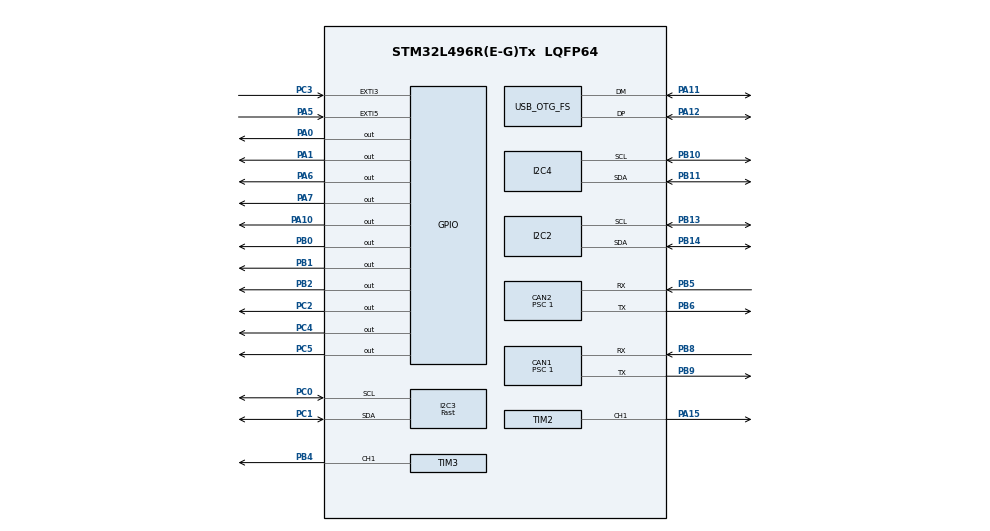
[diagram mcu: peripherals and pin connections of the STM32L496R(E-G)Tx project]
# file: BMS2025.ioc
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CAN1.BS1=CAN_BS1_2TQ
CAN1.CalculateBaudRate=500000
CAN1.CalculateTimeBit=2000
CAN1.CalculateTimeQuantum=500.0
CAN1.Prescaler=1
CAN2.BS1=CAN_BS1_2TQ
CAN2.CalculateBaudRate=500000
CAN2.CalculateTimeBit=2000
CAN2.CalculateTimeQuantum=500.0
CAN2.Prescaler=1
FREERTOS.Tasks01=defaultTask,24,128,StartDefaultTask,Default,NULL,Dynamic,NULL,NULL;Voltage_Monitor,32,128,StartTask02,Default,NULL,Dynamic,NULL,NULL;Temp_Monitoring,40,128,StartTask03,Default,NULL,Dynamic,NULL,NULL;Current_Monitor,24,256,StartTask04,Default,NULL,Dynamic,NULL,NULL;Battery_Data_Tr,32,128,StartTask05,Default,NULL,Dynamic,NULL,NULL;Update_Fan_Spee,32,128,StartTask06,Default,NULL,Dynamic,NULL,NULL
FREERTOS.configTOTAL_HEAP_SIZE=5000
FREERTOS.configUSE_NEWLIB_REENTRANT=1
I2C2.Timing=0x00000508
I2C3.I2C_Speed_Mode=I2C_Fast
I2C3.Timing=0x00000000
I2C4.Timing=0x00000508
Mcu.Family=STM32L4
Mcu.Name=STM32L496R(E-G)Tx
Mcu.Package=LQFP64
NVIC.CAN1_RX0_IRQn=true\:5\:0\:false\:false\:true\:true\:true\:true\:true
NVIC.EXTI3_IRQn=true\:5\:0\:false\:false\:true\:true\:true\:true\:true
NVIC.EXTI9_5_IRQn=true\:5\:0\:false\:false\:true\:true\:true\:true\:true
NVIC.OTG_FS_IRQn=true\:5\:0\:false\:false\:true\:true\:false\:true\:true
NVIC.PriorityGroup=NVIC_PRIORITYGROUP_4
NVIC.TIM1_UP_TIM16_IRQn=true\:15\:0\:false\:false\:true\:false\:false\:true\:true
NVIC.TimeBase=TIM1_UP_TIM16_IRQn
NVIC.TimeBaseIP=TIM1
PA0.Signal=GPIO_Output
PA1.Signal=GPIO_Output
PA10.Signal=GPIO_Output
PA11.Mode=Device_Only
PA11.Signal=USB_OTG_FS_DM
PA12.Mode=Device_Only
PA12.Signal=USB_OTG_FS_DP
PA13\ (JTMS/SWDIO).Mode=Serial_Wire
PA13\ (JTMS/SWDIO).Signal=SYS_JTMS-SWDIO
PA14\ (JTCK/SWCLK).Mode=Serial_Wire
PA14\ (JTCK/SWCLK).Signal=SYS_JTCK-SWCLK
PA15\ (JTDI).Signal=S_TIM2_CH1
PA5.Signal=GPXTI5
PA6.Signal=GPIO_Output
PA7.Signal=GPIO_Output
PB0.Signal=GPIO_Output
PB1.Signal=GPIO_Output
PB10.Mode=I2C
PB10.Signal=I2C4_SCL
PB11.Mode=I2C
PB11.Signal=I2C4_SDA
PB13.Mode=I2C
PB13.Signal=I2C2_SCL
PB14.Mode=I2C
PB14.Signal=I2C2_SDA
PB2.Signal=GPIO_Output
PB4\ (NJTRST).Signal=S_TIM3_CH1
PB5.Mode=CAN_Activate
PB5.Signal=CAN2_RX
PB6.Mode=CAN_Activate
PB6.Signal=CAN2_TX
PB8.Mode=CAN_Activate
PB8.Signal=CAN1_RX
PB9.Mode=CAN_Activate
PB9.Signal=CAN1_TX
PC0.Mode=I2C
PC0.Signal=I2C3_SCL
PC1.Mode=I2C
PC1.Signal=I2C3_SDA
PC2.Signal=GPIO_Output
PC3.Signal=GPXTI3
PC4.Signal=GPIO_Output
PC5.Signal=GPIO_Output
ProjectManager.HeapSize=0x200
ProjectManager.StackSize=0x400
ProjectManager.TargetToolchain=STM32CubeIDE
RCC.ADCFreq_Value=192000000
RCC.AHBFreq_Value=16000000
RCC.APB1CLKDivider=RCC_HCLK_DIV8
RCC.APB1Freq_Value=2000000
RCC.APB1TimFreq_Value=4000000
RCC.APB2Freq_Value=16000000
RCC.APB2TimFreq_Value=16000000
RCC.CK48CLockSelection=RCC_USBCLKSOURCE_HSI48
RCC.CortexFreq_Value=16000000
RCC.HCLKFreq_Value=16000000
RCC.HSE_VALUE=16000000
RCC.HSI48_VALUE=48000000
RCC.HSICalibrationValue=64
RCC.HSI_VALUE=16000000
RCC.LSE_VALUE=32768
RCC.MSICalibrationValue=1
RCC.MSI_VALUE=4000000
RCC.PLLN=40
RCC.PLLSAI1N=24
RCC.PLLSourceVirtual=RCC_PLLSOURCE_HSI
RCC.SYSCLKFreq_VALUE=16000000
RCC.SYSCLKSource=RCC_SYSCLKSOURCE_HSI
RCC.USBFreq_Value=48000000
RCC.VCOOutputFreq_Value=640000000
SH.S_TIM2_CH1.0=TIM2_CH1,PWM Generation1 CH1
SH.S_TIM3_CH1.0=TIM3_CH1,PWM Generation1 CH1
TIM2.Channel-PWM\ Generation1\ CH1=TIM_CHANNEL_1
TIM2.Period=40-1
TIM2.Prescaler=4-1
TIM3.Channel-PWM\ Generation1\ CH1=TIM_CHANNEL_1
TIM3.Period=40-1
TIM3.Prescaler=4-1
USB_DEVICE.CLASS_NAME_FS=CDC
USB_DEVICE.VirtualMode=Cdc
USB_DEVICE.VirtualModeFS=Cdc_FS
USB_OTG_FS.VirtualMode=Device_Only
VP_FREERTOS_VS_CMSIS_V2.Mode=CMSIS_V2
VP_SYS_VS_tim1.Mode=TIM1
VP_USB_DEVICE_VS_USB_DEVICE_CDC_FS.Mode=CDC_FS
board=custom

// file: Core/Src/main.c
/* USER CODE BEGIN Header */
/**
  ******************************************************************************
  * @file           : main.c
  * @brief          : Main program body
  ******************************************************************************
  * @attention
  *
  * Copyright (c) 2025 STMicroelectronics.
  * All rights reserved.
  *
  * This software is licensed under terms that can be found in the LICENSE file
  * in the root directory of this software component.
  * If no LICENSE file comes with this software, it is provided AS-IS.
  *
  ******************************************************************************
  */
/* USER CODE END Header */
#include "main.h"
#include "cmsis_os.h"

CAN_HandleTypeDef hcan1;
CAN_HandleTypeDef hcan2;

I2C_HandleTypeDef hi2c2;
I2C_HandleTypeDef hi2c3;
I2C_HandleTypeDef hi2c4;

TIM_HandleTypeDef htim2;
TIM_HandleTypeDef htim3;

HCD_HandleTypeDef hhcd_USB_OTG_FS;

/* Definitions for defaultTask */
osThreadId_t defaultTaskHandle;
const osThreadAttr_t defaultTask_attributes = {
  .name = "defaultTask",
  .stack_size = 128 * 4,
  .priority = (osPriority_t) osPriorityNormal,
};
/* Definitions for Voltage_Monitor */
osThreadId_t Voltage_MonitorHandle;
const osThreadAttr_t Voltage_Monitor_attributes = {
  .name = "Voltage_Monitor",
  .stack_size = 128 * 4,
  .priority = (osPriority_t) osPriorityAboveNormal,
};
/* Definitions for Temp_Monitoring */
osThreadId_t Temp_MonitoringHandle;
const osThreadAttr_t Temp_Monitoring_attributes = {
  .name = "Temp_Monitoring",
  .stack_size = 128 * 4,
  .priority = (osPriority_t) osPriorityHigh,
};
/* Definitions for Current_Monitor */
osThreadId_t Current_MonitorHandle;
const osThreadAttr_t Current_Monitor_attributes = {
  .name = "Current_Monitor",
  .stack_size = 128 * 4,
  .priority = (osPriority_t) osPriorityNormal,
};
/* Definitions for Battery_Data_Tr */
osThreadId_t Battery_Data_TrHandle;
const osThreadAttr_t Battery_Data_Tr_attributes = {
  .name = "Battery_Data_Tr",
  .stack_size = 128 * 4,
  .priority = (osPriority_t) osPriorityAboveNormal,
};
/* Definitions for Update_Fan_Spee */
osThreadId_t Update_Fan_SpeeHandle;
const osThreadAttr_t Update_Fan_Spee_attributes = {
  .name = "Update_Fan_Spee",
  .stack_size = 128 * 4,
  .priority = (osPriority_t) osPriorityAboveNormal,
};

void SystemClock_Config(void);
static void MX_GPIO_Init(void);
static void MX_CAN1_Init(void);
static void MX_CAN2_Init(void);
static void MX_I2C2_Init(void);
static void MX_I2C3_Init(void);
static void MX_I2C4_Init(void);
static void MX_TIM2_Init(void);
static void MX_TIM3_Init(void);
static void MX_USB_OTG_FS_HCD_Init(void);
void StartDefaultTask(void *argument);
void StartTask02(void *argument);
void StartTask03(void *argument);
void StartTask04(void *argument);
void StartTask05(void *argument);
void StartTask06(void *argument);

int main(void)
{

  /* MCU Configuration--------------------------------------------------------*/

  /* Reset of all peripherals, Initializes the Flash interface and the Systick. */
  HAL_Init();

  /* Configure the system clock */
  SystemClock_Config();

  /* Initialize all configured peripherals */
  MX_GPIO_Init();
  MX_CAN1_Init();
  MX_CAN2_Init();
  MX_I2C2_Init();
  MX_I2C3_Init();
  MX_I2C4_Init();
  MX_TIM2_Init();
  MX_TIM3_Init();
  MX_USB_OTG_FS_HCD_Init();

  /* Init scheduler */
  osKernelInitialize();

  /* Create the thread(s) */
  /* creation of defaultTask */
  defaultTaskHandle = osThreadNew(StartDefaultTask, NULL, &defaultTask_attributes);

  /* creation of Voltage_Monitor */
  Voltage_MonitorHandle = osThreadNew(StartTask02, NULL, &Voltage_Monitor_attributes);

  /* creation of Temp_Monitoring */
  Temp_MonitoringHandle = osThreadNew(StartTask03, NULL, &Temp_Monitoring_attributes);

  /* creation of Current_Monitor */
  Current_MonitorHandle = osThreadNew(StartTask04, NULL, &Current_Monitor_attributes);

  /* creation of Battery_Data_Tr */
  Battery_Data_TrHandle = osThreadNew(StartTask05, NULL, &Battery_Data_Tr_attributes);

  /* creation of Update_Fan_Spee */
  Update_Fan_SpeeHandle = osThreadNew(StartTask06, NULL, &Update_Fan_Spee_attributes);

  /* Start scheduler */
  osKernelStart();

  /* We should never get here as control is now taken by the scheduler */

  /* Infinite loop */
  while (1)
  {

  }
}

void SystemClock_Config(void)
{
  RCC_OscInitTypeDef RCC_OscInitStruct = {0};
  RCC_ClkInitTypeDef RCC_ClkInitStruct = {0};

  /** Configure the main internal regulator output voltage
  */
  if (HAL_PWREx_ControlVoltageScaling(PWR_REGULATOR_VOLTAGE_SCALE1) != HAL_OK)
  {
    Error_Handler();
  }

  /** Initializes the RCC Oscillators according to the specified parameters
  * in the RCC_OscInitTypeDef structure.
  */
  RCC_OscInitStruct.OscillatorType = RCC_OSCILLATORTYPE_HSE;
  RCC_OscInitStruct.HSEState = RCC_HSE_ON;
  RCC_OscInitStruct.PLL.PLLState = RCC_PLL_ON;
  RCC_OscInitStruct.PLL.PLLSource = RCC_PLLSOURCE_HSE;
  RCC_OscInitStruct.PLL.PLLM = 1;
  RCC_OscInitStruct.PLL.PLLN = 8;
  RCC_OscInitStruct.PLL.PLLP = RCC_PLLP_DIV2;
  RCC_OscInitStruct.PLL.PLLQ = RCC_PLLQ_DIV2;
  RCC_OscInitStruct.PLL.PLLR = RCC_PLLR_DIV2;
  if (HAL_RCC_OscConfig(&RCC_OscInitStruct) != HAL_OK)
  {
    Error_Handler();
  }

  /** Initializes the CPU, AHB and APB buses clocks
  */
  RCC_ClkInitStruct.ClockType = RCC_CLOCKTYPE_HCLK|RCC_CLOCKTYPE_SYSCLK
                              |RCC_CLOCKTYPE_PCLK1|RCC_CLOCKTYPE_PCLK2;
  RCC_ClkInitStruct.SYSCLKSource = RCC_SYSCLKSOURCE_PLLCLK;
  RCC_ClkInitStruct.AHBCLKDivider = RCC_SYSCLK_DIV1;
  RCC_ClkInitStruct.APB1CLKDivider = RCC_HCLK_DIV16;
  RCC_ClkInitStruct.APB2CLKDivider = RCC_HCLK_DIV1;

  if (HAL_RCC_ClockConfig(&RCC_ClkInitStruct, FLASH_LATENCY_3) != HAL_OK)
  {
    Error_Handler();
  }
}

static void MX_CAN1_Init(void)
{

  hcan1.Instance = CAN1;
  hcan1.Init.Prescaler = 2;
  hcan1.Init.Mode = CAN_MODE_NORMAL;
  hcan1.Init.SyncJumpWidth = CAN_SJW_1TQ;
  hcan1.Init.TimeSeg1 = CAN_BS1_2TQ;
  hcan1.Init.TimeSeg2 = CAN_BS2_1TQ;
  hcan1.Init.TimeTriggeredMode = DISABLE;
  hcan1.Init.AutoBusOff = DISABLE;
  hcan1.Init.AutoWakeUp = DISABLE;
  hcan1.Init.AutoRetransmission = DISABLE;
  hcan1.Init.ReceiveFifoLocked = DISABLE;
  hcan1.Init.TransmitFifoPriority = DISABLE;
  if (HAL_CAN_Init(&hcan1) != HAL_OK)
  {
    Error_Handler();
  }

}

static void MX_CAN2_Init(void)
{

  hcan2.Instance = CAN2;
  hcan2.Init.Prescaler = 10;
  hcan2.Init.Mode = CAN_MODE_NORMAL;
  hcan2.Init.SyncJumpWidth = CAN_SJW_1TQ;
  hcan2.Init.TimeSeg1 = CAN_BS1_14TQ;
  hcan2.Init.TimeSeg2 = CAN_BS2_1TQ;
  hcan2.Init.TimeTriggeredMode = DISABLE;
  hcan2.Init.AutoBusOff = DISABLE;
  hcan2.Init.AutoWakeUp = DISABLE;
  hcan2.Init.AutoRetransmission = DISABLE;
  hcan2.Init.ReceiveFifoLocked = DISABLE;
  hcan2.Init.TransmitFifoPriority = DISABLE;
  if (HAL_CAN_Init(&hcan2) != HAL_OK)
  {
    Error_Handler();
  }

}

static void MX_I2C2_Init(void)
{

  hi2c2.Instance = I2C2;
  hi2c2.Init.Timing = 0x00100D14;
  hi2c2.Init.OwnAddress1 = 0;
  hi2c2.Init.AddressingMode = I2C_ADDRESSINGMODE_7BIT;
  hi2c2.Init.DualAddressMode = I2C_DUALADDRESS_DISABLE;
  hi2c2.Init.OwnAddress2 = 0;
  hi2c2.Init.OwnAddress2Masks = I2C_OA2_NOMASK;
  hi2c2.Init.GeneralCallMode = I2C_GENERALCALL_DISABLE;
  hi2c2.Init.NoStretchMode = I2C_NOSTRETCH_DISABLE;
  if (HAL_I2C_Init(&hi2c2) != HAL_OK)
  {
    Error_Handler();
  }

  /** Configure Analogue filter
  */
  if (HAL_I2CEx_ConfigAnalogFilter(&hi2c2, I2C_ANALOGFILTER_ENABLE) != HAL_OK)
  {
    Error_Handler();
  }

  /** Configure Digital filter
  */
  if (HAL_I2CEx_ConfigDigitalFilter(&hi2c2, 0) != HAL_OK)
  {
    Error_Handler();
  }

}

static void MX_I2C3_Init(void)
{

  hi2c3.Instance = I2C3;
  hi2c3.Init.Timing = 0x00100D14;
  hi2c3.Init.OwnAddress1 = 0;
  hi2c3.Init.AddressingMode = I2C_ADDRESSINGMODE_7BIT;
  hi2c3.Init.DualAddressMode = I2C_DUALADDRESS_DISABLE;
  hi2c3.Init.OwnAddress2 = 0;
  hi2c3.Init.OwnAddress2Masks = I2C_OA2_NOMASK;
  hi2c3.Init.GeneralCallMode = I2C_GENERALCALL_DISABLE;
  hi2c3.Init.NoStretchMode = I2C_NOSTRETCH_DISABLE;
  if (HAL_I2C_Init(&hi2c3) != HAL_OK)
  {
    Error_Handler();
  }

  /** Configure Analogue filter
  */
  if (HAL_I2CEx_ConfigAnalogFilter(&hi2c3, I2C_ANALOGFILTER_ENABLE) != HAL_OK)
  {
    Error_Handler();
  }

  /** Configure Digital filter
  */
  if (HAL_I2CEx_ConfigDigitalFilter(&hi2c3, 0) != HAL_OK)
  {
    Error_Handler();
  }

}

static void MX_I2C4_Init(void)
{

  hi2c4.Instance = I2C4;
  hi2c4.Init.Timing = 0x00100D14;
  hi2c4.Init.OwnAddress1 = 0;
  hi2c4.Init.AddressingMode = I2C_ADDRESSINGMODE_7BIT;
  hi2c4.Init.DualAddressMode = I2C_DUALADDRESS_DISABLE;
  hi2c4.Init.OwnAddress2 = 0;
  hi2c4.Init.OwnAddress2Masks = I2C_OA2_NOMASK;
  hi2c4.Init.GeneralCallMode = I2C_GENERALCALL_DISABLE;
  hi2c4.Init.NoStretchMode = I2C_NOSTRETCH_DISABLE;
  if (HAL_I2C_Init(&hi2c4) != HAL_OK)
  {
    Error_Handler();
  }

  /** Configure Analogue filter
  */
  if (HAL_I2CEx_ConfigAnalogFilter(&hi2c4, I2C_ANALOGFILTER_ENABLE) != HAL_OK)
  {
    Error_Handler();
  }

  /** Configure Digital filter
  */
  if (HAL_I2CEx_ConfigDigitalFilter(&hi2c4, 0) != HAL_OK)
  {
    Error_Handler();
  }

}

static void MX_TIM2_Init(void)
{

  TIM_MasterConfigTypeDef sMasterConfig = {0};
  TIM_OC_InitTypeDef sConfigOC = {0};

  htim2.Instance = TIM2;
  htim2.Init.Prescaler = 0;
  htim2.Init.CounterMode = TIM_COUNTERMODE_UP;
  htim2.Init.Period = 4294967295;
  htim2.Init.ClockDivision = TIM_CLOCKDIVISION_DIV1;
  htim2.Init.AutoReloadPreload = TIM_AUTORELOAD_PRELOAD_DISABLE;
  if (HAL_TIM_PWM_Init(&htim2) != HAL_OK)
  {
    Error_Handler();
  }
  sMasterConfig.MasterOutputTrigger = TIM_TRGO_RESET;
  sMasterConfig.MasterSlaveMode = TIM_MASTERSLAVEMODE_DISABLE;
  if (HAL_TIMEx_MasterConfigSynchronization(&htim2, &sMasterConfig) != HAL_OK)
  {
    Error_Handler();
  }
  sConfigOC.OCMode = TIM_OCMODE_PWM1;
  sConfigOC.Pulse = 0;
  sConfigOC.OCPolarity = TIM_OCPOLARITY_HIGH;
  sConfigOC.OCFastMode = TIM_OCFAST_DISABLE;
  if (HAL_TIM_PWM_ConfigChannel(&htim2, &sConfigOC, TIM_CHANNEL_1) != HAL_OK)
  {
    Error_Handler();
  }
  HAL_TIM_MspPostInit(&htim2);

}

static void MX_TIM3_Init(void)
{

  TIM_MasterConfigTypeDef sMasterConfig = {0};
  TIM_OC_InitTypeDef sConfigOC = {0};

  htim3.Instance = TIM3;
  htim3.Init.Prescaler = 0;
  htim3.Init.CounterMode = TIM_COUNTERMODE_UP;
  htim3.Init.Period = 65535;
  htim3.Init.ClockDivision = TIM_CLOCKDIVISION_DIV1;
  htim3.Init.AutoReloadPreload = TIM_AUTORELOAD_PRELOAD_DISABLE;
  if (HAL_TIM_PWM_Init(&htim3) != HAL_OK)
  {
    Error_Handler();
  }
  sMasterConfig.MasterOutputTrigger = TIM_TRGO_RESET;
  sMasterConfig.MasterSlaveMode = TIM_MASTERSLAVEMODE_DISABLE;
  if (HAL_TIMEx_MasterConfigSynchronization(&htim3, &sMasterConfig) != HAL_OK)
  {
    Error_Handler();
  }
  sConfigOC.OCMode = TIM_OCMODE_PWM1;
  sConfigOC.Pulse = 0;
  sConfigOC.OCPolarity = TIM_OCPOLARITY_HIGH;
  sConfigOC.OCFastMode = TIM_OCFAST_DISABLE;
  if (HAL_TIM_PWM_ConfigChannel(&htim3, &sConfigOC, TIM_CHANNEL_1) != HAL_OK)
  {
    Error_Handler();
  }
  HAL_TIM_MspPostInit(&htim3);

}

static void MX_USB_OTG_FS_HCD_Init(void)
{

  hhcd_USB_OTG_FS.Instance = USB_OTG_FS;
  hhcd_USB_OTG_FS.Init.Host_channels = 12;
  hhcd_USB_OTG_FS.Init.speed = HCD_SPEED_FULL;
  hhcd_USB_OTG_FS.Init.dma_enable = DISABLE;
  hhcd_USB_OTG_FS.Init.phy_itface = HCD_PHY_EMBEDDED;
  hhcd_USB_OTG_FS.Init.Sof_enable = DISABLE;
  if (HAL_HCD_Init(&hhcd_USB_OTG_FS) != HAL_OK)
  {
    Error_Handler();
  }

}

static void MX_GPIO_Init(void)
{
  GPIO_InitTypeDef GPIO_InitStruct = {0};

  /* GPIO Ports Clock Enable */
  __HAL_RCC_GPIOH_CLK_ENABLE();
  __HAL_RCC_GPIOC_CLK_ENABLE();
  __HAL_RCC_GPIOA_CLK_ENABLE();
  __HAL_RCC_GPIOB_CLK_ENABLE();

  /*Configure GPIO pin Output Level */
  HAL_GPIO_WritePin(GPIOC, GPIO_PIN_2|GPIO_PIN_4|GPIO_PIN_5, GPIO_PIN_RESET);

  /*Configure GPIO pin Output Level */
  HAL_GPIO_WritePin(GPIOA, GPIO_PIN_0|GPIO_PIN_1|GPIO_PIN_6|GPIO_PIN_7
                          |GPIO_PIN_10, GPIO_PIN_RESET);

  /*Configure GPIO pin Output Level */
  HAL_GPIO_WritePin(GPIOB, GPIO_PIN_0|GPIO_PIN_1|GPIO_PIN_2, GPIO_PIN_RESET);

  /*Configure GPIO pins : PC2 PC4 PC5 */
  GPIO_InitStruct.Pin = GPIO_PIN_2|GPIO_PIN_4|GPIO_PIN_5;
  GPIO_InitStruct.Mode = GPIO_MODE_OUTPUT_PP;
  GPIO_InitStruct.Pull = GPIO_NOPULL;
  GPIO_InitStruct.Speed = GPIO_SPEED_FREQ_LOW;
  HAL_GPIO_Init(GPIOC, &GPIO_InitStruct);

  /*Configure GPIO pin : PC3 */
  GPIO_InitStruct.Pin = GPIO_PIN_3;
  GPIO_InitStruct.Mode = GPIO_MODE_IT_RISING;
  GPIO_InitStruct.Pull = GPIO_NOPULL;
  HAL_GPIO_Init(GPIOC, &GPIO_InitStruct);

  /*Configure GPIO pins : PA0 PA1 PA6 PA7
                           PA10 */
  GPIO_InitStruct.Pin = GPIO_PIN_0|GPIO_PIN_1|GPIO_PIN_6|GPIO_PIN_7
                          |GPIO_PIN_10;
  GPIO_InitStruct.Mode = GPIO_MODE_OUTPUT_PP;
  GPIO_InitStruct.Pull = GPIO_NOPULL;
  GPIO_InitStruct.Speed = GPIO_SPEED_FREQ_LOW;
  HAL_GPIO_Init(GPIOA, &GPIO_InitStruct);

  /*Configure GPIO pin : PA5 */
  GPIO_InitStruct.Pin = GPIO_PIN_5;
  GPIO_InitStruct.Mode = GPIO_MODE_IT_RISING;
  GPIO_InitStruct.Pull = GPIO_NOPULL;
  HAL_GPIO_Init(GPIOA, &GPIO_InitStruct);

  /*Configure GPIO pins : PB0 PB1 PB2 */
  GPIO_InitStruct.Pin = GPIO_PIN_0|GPIO_PIN_1|GPIO_PIN_2;
  GPIO_InitStruct.Mode = GPIO_MODE_OUTPUT_PP;
  GPIO_InitStruct.Pull = GPIO_NOPULL;
  GPIO_InitStruct.Speed = GPIO_SPEED_FREQ_LOW;
  HAL_GPIO_Init(GPIOB, &GPIO_InitStruct);

  /* EXTI interrupt init*/
  HAL_NVIC_SetPriority(EXTI3_IRQn, 5, 0);
  HAL_NVIC_EnableIRQ(EXTI3_IRQn);

  HAL_NVIC_SetPriority(EXTI9_5_IRQn, 5, 0);
  HAL_NVIC_EnableIRQ(EXTI9_5_IRQn);

}

void StartDefaultTask(void *argument)
{
  for(;;)
  {
    osDelay(1);
  }
}

void StartTask02(void *argument)
{
  for(;;)
  {
    osDelay(1);
  }
}

void StartTask03(void *argument)
{
  for(;;)
  {
    osDelay(1);
  }
}

void StartTask04(void *argument)
{
  for(;;)
  {
    osDelay(1);
  }
}

void StartTask05(void *argument)
{
  for(;;)
  {
    osDelay(1);
  }
}

void StartTask06(void *argument)
{
  for(;;)
  {
    osDelay(1);
  }
}

void HAL_TIM_PeriodElapsedCallback(TIM_HandleTypeDef *htim)
{
  if (htim->Instance == TIM1)
  {
    HAL_IncTick();
  }
}

void Error_Handler(void)
{
  __disable_irq();
  while (1)
  {
  }
}
